VERSION 5.7 ;
  NOWIREEXTENSIONATPIN ON ;
  DIVIDERCHAR "/" ;
  BUSBITCHARS "[]" ;
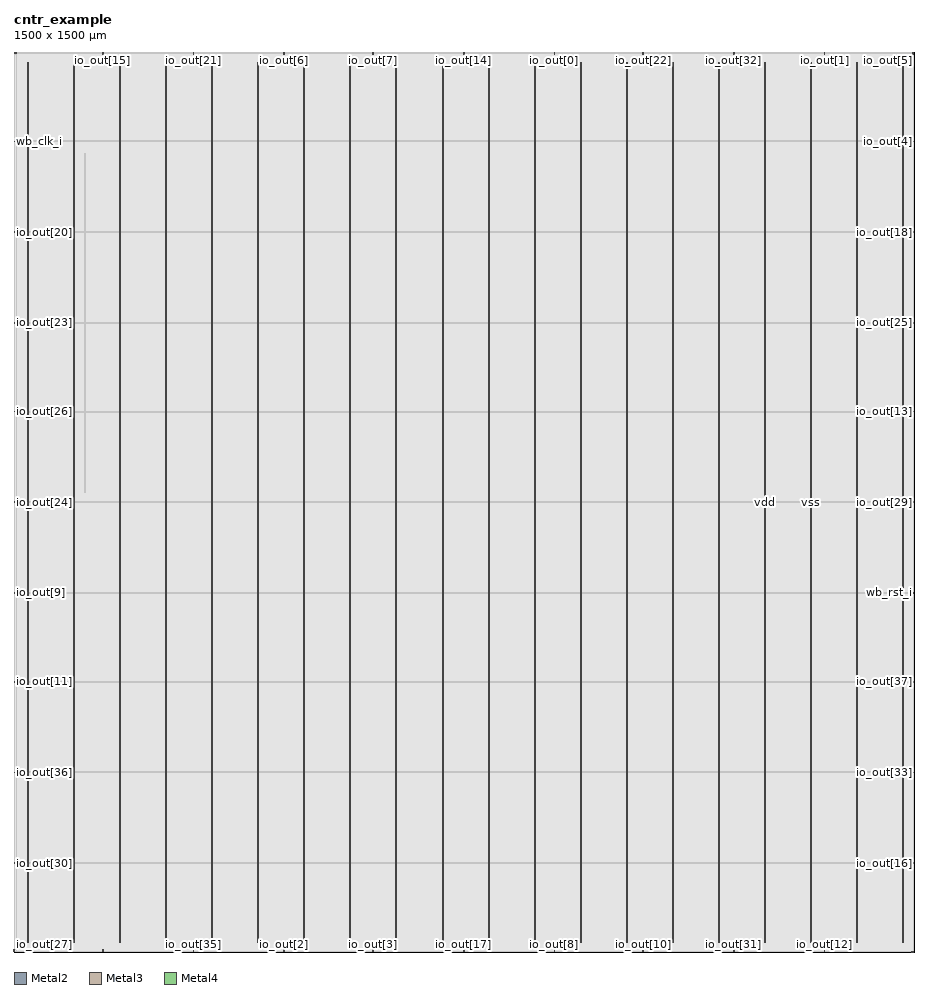
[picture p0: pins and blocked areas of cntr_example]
MACRO cntr_example
  CLASS BLOCK ;
  FOREIGN cntr_example ;
  ORIGIN 0.000 0.000 ;
  SIZE 1500.000 BY 1500.000 ;
  PIN io_out[0]
    DIRECTION OUTPUT TRISTATE ;
    USE SIGNAL ;
    PORT
      LAYER Metal2 ;
        RECT 900.200 1496.000 901.320 1499.000 ;
    END
  END io_out[0]
  PIN io_out[10]
    DIRECTION OUTPUT TRISTATE ;
    USE SIGNAL ;
    PORT
      LAYER Metal2 ;
        RECT 1048.040 1.000 1049.160 4.000 ;
    END
  END io_out[10]
  PIN io_out[11]
    DIRECTION OUTPUT TRISTATE ;
    USE SIGNAL ;
    PORT
      LAYER Metal3 ;
        RECT 1.000 449.960 4.000 451.080 ;
    END
  END io_out[11]
  PIN io_out[12]
    DIRECTION OUTPUT TRISTATE ;
    USE SIGNAL ;
    PORT
      LAYER Metal2 ;
        RECT 1350.440 1.000 1351.560 4.000 ;
    END
  END io_out[12]
  PIN io_out[13]
    DIRECTION OUTPUT TRISTATE ;
    USE SIGNAL ;
    PORT
      LAYER Metal3 ;
        RECT 1496.000 900.200 1499.000 901.320 ;
    END
  END io_out[13]
  PIN io_out[14]
    DIRECTION OUTPUT TRISTATE ;
    USE SIGNAL ;
    PORT
      LAYER Metal2 ;
        RECT 749.000 1496.000 750.120 1499.000 ;
    END
  END io_out[14]
  PIN io_out[15]
    DIRECTION OUTPUT TRISTATE ;
    USE SIGNAL ;
    PORT
      LAYER Metal2 ;
        RECT 147.560 1496.000 148.680 1499.000 ;
    END
  END io_out[15]
  PIN io_out[16]
    DIRECTION OUTPUT TRISTATE ;
    USE SIGNAL ;
    PORT
      LAYER Metal3 ;
        RECT 1496.000 147.560 1499.000 148.680 ;
    END
  END io_out[16]
  PIN io_out[17]
    DIRECTION OUTPUT TRISTATE ;
    USE SIGNAL ;
    PORT
      LAYER Metal2 ;
        RECT 749.000 1.000 750.120 4.000 ;
    END
  END io_out[17]
  PIN io_out[18]
    DIRECTION OUTPUT TRISTATE ;
    USE SIGNAL ;
    PORT
      LAYER Metal3 ;
        RECT 1496.000 1199.240 1499.000 1200.360 ;
    END
  END io_out[18]
  PIN io_out[19]
    DIRECTION OUTPUT TRISTATE ;
    USE SIGNAL ;
    PORT
      LAYER Metal3 ;
        RECT 1496.000 -0.280 1499.000 0.840 ;
    END
  END io_out[19]
  PIN io_out[1]
    DIRECTION OUTPUT TRISTATE ;
    USE SIGNAL ;
    PORT
      LAYER Metal2 ;
        RECT 1350.440 1496.000 1351.560 1499.000 ;
    END
  END io_out[1]
  PIN io_out[20]
    DIRECTION OUTPUT TRISTATE ;
    USE SIGNAL ;
    PORT
      LAYER Metal3 ;
        RECT 1.000 1199.240 4.000 1200.360 ;
    END
  END io_out[20]
  PIN io_out[21]
    DIRECTION OUTPUT TRISTATE ;
    USE SIGNAL ;
    PORT
      LAYER Metal2 ;
        RECT 298.760 1496.000 299.880 1499.000 ;
    END
  END io_out[21]
  PIN io_out[22]
    DIRECTION OUTPUT TRISTATE ;
    USE SIGNAL ;
    PORT
      LAYER Metal2 ;
        RECT 1048.040 1496.000 1049.160 1499.000 ;
    END
  END io_out[22]
  PIN io_out[23]
    DIRECTION OUTPUT TRISTATE ;
    USE SIGNAL ;
    PORT
      LAYER Metal3 ;
        RECT 1.000 1048.040 4.000 1049.160 ;
    END
  END io_out[23]
  PIN io_out[24]
    DIRECTION OUTPUT TRISTATE ;
    USE SIGNAL ;
    PORT
      LAYER Metal3 ;
        RECT 1.000 749.000 4.000 750.120 ;
    END
  END io_out[24]
  PIN io_out[25]
    DIRECTION OUTPUT TRISTATE ;
    USE SIGNAL ;
    PORT
      LAYER Metal3 ;
        RECT 1496.000 1048.040 1499.000 1049.160 ;
    END
  END io_out[25]
  PIN io_out[26]
    DIRECTION OUTPUT TRISTATE ;
    USE SIGNAL ;
    PORT
      LAYER Metal3 ;
        RECT 1.000 900.200 4.000 901.320 ;
    END
  END io_out[26]
  PIN io_out[27]
    DIRECTION OUTPUT TRISTATE ;
    USE SIGNAL ;
    PORT
      LAYER Metal2 ;
        RECT -0.280 1.000 0.840 4.000 ;
    END
  END io_out[27]
  PIN io_out[28]
    DIRECTION OUTPUT TRISTATE ;
    USE SIGNAL ;
    PORT
      LAYER Metal3 ;
        RECT 1.000 1498.280 4.000 1499.400 ;
    END
  END io_out[28]
  PIN io_out[29]
    DIRECTION OUTPUT TRISTATE ;
    USE SIGNAL ;
    PORT
      LAYER Metal3 ;
        RECT 1496.000 749.000 1499.000 750.120 ;
    END
  END io_out[29]
  PIN io_out[2]
    DIRECTION OUTPUT TRISTATE ;
    USE SIGNAL ;
    PORT
      LAYER Metal2 ;
        RECT 449.960 1.000 451.080 4.000 ;
    END
  END io_out[2]
  PIN io_out[30]
    DIRECTION OUTPUT TRISTATE ;
    USE SIGNAL ;
    PORT
      LAYER Metal3 ;
        RECT 1.000 147.560 4.000 148.680 ;
    END
  END io_out[30]
  PIN io_out[31]
    DIRECTION OUTPUT TRISTATE ;
    USE SIGNAL ;
    PORT
      LAYER Metal2 ;
        RECT 1199.240 1.000 1200.360 4.000 ;
    END
  END io_out[31]
  PIN io_out[32]
    DIRECTION OUTPUT TRISTATE ;
    USE SIGNAL ;
    PORT
      LAYER Metal2 ;
        RECT 1199.240 1496.000 1200.360 1499.000 ;
    END
  END io_out[32]
  PIN io_out[33]
    DIRECTION OUTPUT TRISTATE ;
    USE SIGNAL ;
    PORT
      LAYER Metal3 ;
        RECT 1496.000 298.760 1499.000 299.880 ;
    END
  END io_out[33]
  PIN io_out[34]
    DIRECTION OUTPUT TRISTATE ;
    USE SIGNAL ;
    PORT
      LAYER Metal2 ;
        RECT 147.560 1.000 148.680 4.000 ;
    END
  END io_out[34]
  PIN io_out[35]
    DIRECTION OUTPUT TRISTATE ;
    USE SIGNAL ;
    PORT
      LAYER Metal2 ;
        RECT 298.760 1.000 299.880 4.000 ;
    END
  END io_out[35]
  PIN io_out[36]
    DIRECTION OUTPUT TRISTATE ;
    USE SIGNAL ;
    PORT
      LAYER Metal3 ;
        RECT 1.000 298.760 4.000 299.880 ;
    END
  END io_out[36]
  PIN io_out[37]
    DIRECTION OUTPUT TRISTATE ;
    USE SIGNAL ;
    PORT
      LAYER Metal3 ;
        RECT 1496.000 449.960 1499.000 451.080 ;
    END
  END io_out[37]
  PIN io_out[3]
    DIRECTION OUTPUT TRISTATE ;
    USE SIGNAL ;
    PORT
      LAYER Metal2 ;
        RECT 597.800 1.000 598.920 4.000 ;
    END
  END io_out[3]
  PIN io_out[4]
    DIRECTION OUTPUT TRISTATE ;
    USE SIGNAL ;
    PORT
      LAYER Metal3 ;
        RECT 1496.000 1350.440 1499.000 1351.560 ;
    END
  END io_out[4]
  PIN io_out[5]
    DIRECTION OUTPUT TRISTATE ;
    USE SIGNAL ;
    PORT
      LAYER Metal2 ;
        RECT 1498.280 1496.000 1499.400 1499.000 ;
    END
  END io_out[5]
  PIN io_out[6]
    DIRECTION OUTPUT TRISTATE ;
    USE SIGNAL ;
    PORT
      LAYER Metal2 ;
        RECT 449.960 1496.000 451.080 1499.000 ;
    END
  END io_out[6]
  PIN io_out[7]
    DIRECTION OUTPUT TRISTATE ;
    USE SIGNAL ;
    PORT
      LAYER Metal2 ;
        RECT 597.800 1496.000 598.920 1499.000 ;
    END
  END io_out[7]
  PIN io_out[8]
    DIRECTION OUTPUT TRISTATE ;
    USE SIGNAL ;
    PORT
      LAYER Metal2 ;
        RECT 900.200 1.000 901.320 4.000 ;
    END
  END io_out[8]
  PIN io_out[9]
    DIRECTION OUTPUT TRISTATE ;
    USE SIGNAL ;
    PORT
      LAYER Metal3 ;
        RECT 1.000 597.800 4.000 598.920 ;
    END
  END io_out[9]
  PIN vdd
    DIRECTION INOUT ;
    USE POWER ;
    PORT
      LAYER Metal4 ;
        RECT 22.240 15.380 23.840 1482.060 ;
    END
    PORT
      LAYER Metal4 ;
        RECT 175.840 15.380 177.440 1482.060 ;
    END
    PORT
      LAYER Metal4 ;
        RECT 329.440 15.380 331.040 1482.060 ;
    END
    PORT
      LAYER Metal4 ;
        RECT 483.040 15.380 484.640 1482.060 ;
    END
    PORT
      LAYER Metal4 ;
        RECT 636.640 15.380 638.240 1482.060 ;
    END
    PORT
      LAYER Metal4 ;
        RECT 790.240 15.380 791.840 1482.060 ;
    END
    PORT
      LAYER Metal4 ;
        RECT 943.840 15.380 945.440 1482.060 ;
    END
    PORT
      LAYER Metal4 ;
        RECT 1097.440 15.380 1099.040 1482.060 ;
    END
    PORT
      LAYER Metal4 ;
        RECT 1251.040 15.380 1252.640 1482.060 ;
    END
    PORT
      LAYER Metal4 ;
        RECT 1404.640 15.380 1406.240 1482.060 ;
    END
  END vdd
  PIN vss
    DIRECTION INOUT ;
    USE GROUND ;
    PORT
      LAYER Metal4 ;
        RECT 99.040 15.380 100.640 1482.060 ;
    END
    PORT
      LAYER Metal4 ;
        RECT 252.640 15.380 254.240 1482.060 ;
    END
    PORT
      LAYER Metal4 ;
        RECT 406.240 15.380 407.840 1482.060 ;
    END
    PORT
      LAYER Metal4 ;
        RECT 559.840 15.380 561.440 1482.060 ;
    END
    PORT
      LAYER Metal4 ;
        RECT 713.440 15.380 715.040 1482.060 ;
    END
    PORT
      LAYER Metal4 ;
        RECT 867.040 15.380 868.640 1482.060 ;
    END
    PORT
      LAYER Metal4 ;
        RECT 1020.640 15.380 1022.240 1482.060 ;
    END
    PORT
      LAYER Metal4 ;
        RECT 1174.240 15.380 1175.840 1482.060 ;
    END
    PORT
      LAYER Metal4 ;
        RECT 1327.840 15.380 1329.440 1482.060 ;
    END
    PORT
      LAYER Metal4 ;
        RECT 1481.440 15.380 1483.040 1482.060 ;
    END
  END vss
  PIN wb_clk_i
    DIRECTION INPUT ;
    USE SIGNAL ;
    PORT
      LAYER Metal3 ;
        RECT 1.000 1350.440 4.000 1351.560 ;
    END
  END wb_clk_i
  PIN wb_rst_i
    DIRECTION INPUT ;
    USE SIGNAL ;
    PORT
      LAYER Metal3 ;
        RECT 1496.000 597.800 1499.000 598.920 ;
    END
  END wb_rst_i
  OBS
      LAYER Metal1 ;
        RECT 6.720 15.380 1492.960 1482.060 ;
      LAYER Metal2 ;
        RECT 0.700 1495.700 147.260 1496.740 ;
        RECT 148.980 1495.700 298.460 1496.740 ;
        RECT 300.180 1495.700 449.660 1496.740 ;
        RECT 451.380 1495.700 597.500 1496.740 ;
        RECT 599.220 1495.700 748.700 1496.740 ;
        RECT 750.420 1495.700 899.900 1496.740 ;
        RECT 901.620 1495.700 1047.740 1496.740 ;
        RECT 1049.460 1495.700 1198.940 1496.740 ;
        RECT 1200.660 1495.700 1350.140 1496.740 ;
        RECT 1351.860 1495.700 1497.980 1496.740 ;
        RECT 0.700 4.300 1498.420 1495.700 ;
        RECT 1.140 0.700 147.260 4.300 ;
        RECT 148.980 0.700 298.460 4.300 ;
        RECT 300.180 0.700 449.660 4.300 ;
        RECT 451.380 0.700 597.500 4.300 ;
        RECT 599.220 0.700 748.700 4.300 ;
        RECT 750.420 0.700 899.900 4.300 ;
        RECT 901.620 0.700 1047.740 4.300 ;
        RECT 1049.460 0.700 1198.940 4.300 ;
        RECT 1200.660 0.700 1350.140 4.300 ;
        RECT 1351.860 0.700 1498.420 4.300 ;
        RECT 0.700 0.650 1498.420 0.700 ;
      LAYER Metal3 ;
        RECT 4.300 1497.980 1498.470 1498.420 ;
        RECT 3.500 1351.860 1498.470 1497.980 ;
        RECT 4.300 1350.140 1495.700 1351.860 ;
        RECT 3.500 1200.660 1498.470 1350.140 ;
        RECT 4.300 1198.940 1495.700 1200.660 ;
        RECT 3.500 1049.460 1498.470 1198.940 ;
        RECT 4.300 1047.740 1495.700 1049.460 ;
        RECT 3.500 901.620 1498.470 1047.740 ;
        RECT 4.300 899.900 1495.700 901.620 ;
        RECT 3.500 750.420 1498.470 899.900 ;
        RECT 4.300 748.700 1495.700 750.420 ;
        RECT 3.500 599.220 1498.470 748.700 ;
        RECT 4.300 597.500 1495.700 599.220 ;
        RECT 3.500 451.380 1498.470 597.500 ;
        RECT 4.300 449.660 1495.700 451.380 ;
        RECT 3.500 300.180 1498.470 449.660 ;
        RECT 4.300 298.460 1495.700 300.180 ;
        RECT 3.500 148.980 1498.470 298.460 ;
        RECT 4.300 147.260 1495.700 148.980 ;
        RECT 3.500 1.140 1498.470 147.260 ;
        RECT 3.500 0.700 1495.700 1.140 ;
      LAYER Metal4 ;
        RECT 118.300 765.610 118.580 1330.470 ;
  END
END cntr_example
END LIBRARY

